VERSION 5.7 ;
DIVIDERCHAR "/" ;
BUSBITCHARS "[]" ;

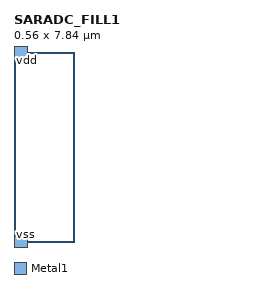
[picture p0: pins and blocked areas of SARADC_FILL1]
MACRO SARADC_FILL1
  CLASS BLOCK ;
  FOREIGN SARADC_FILL1 ;
  ORIGIN 0.000 0.000 ;
  SIZE 0.560 BY 7.840 ;
  SYMMETRY X Y R90 ;
  PIN vdd
    DIRECTION INOUT ;
    USE POWER ;
    PORT
      LAYER Metal1 ;
        RECT 0.000 7.610 0.560 8.070 ;
    END
  END vdd
  PIN vss
    DIRECTION INOUT ;
    USE GROUND ;
    PORT
      LAYER Metal1 ;
        RECT 0.000 -0.230 0.560 0.230 ;
    END
  END vss
END SARADC_FILL1

END LIBRARY
